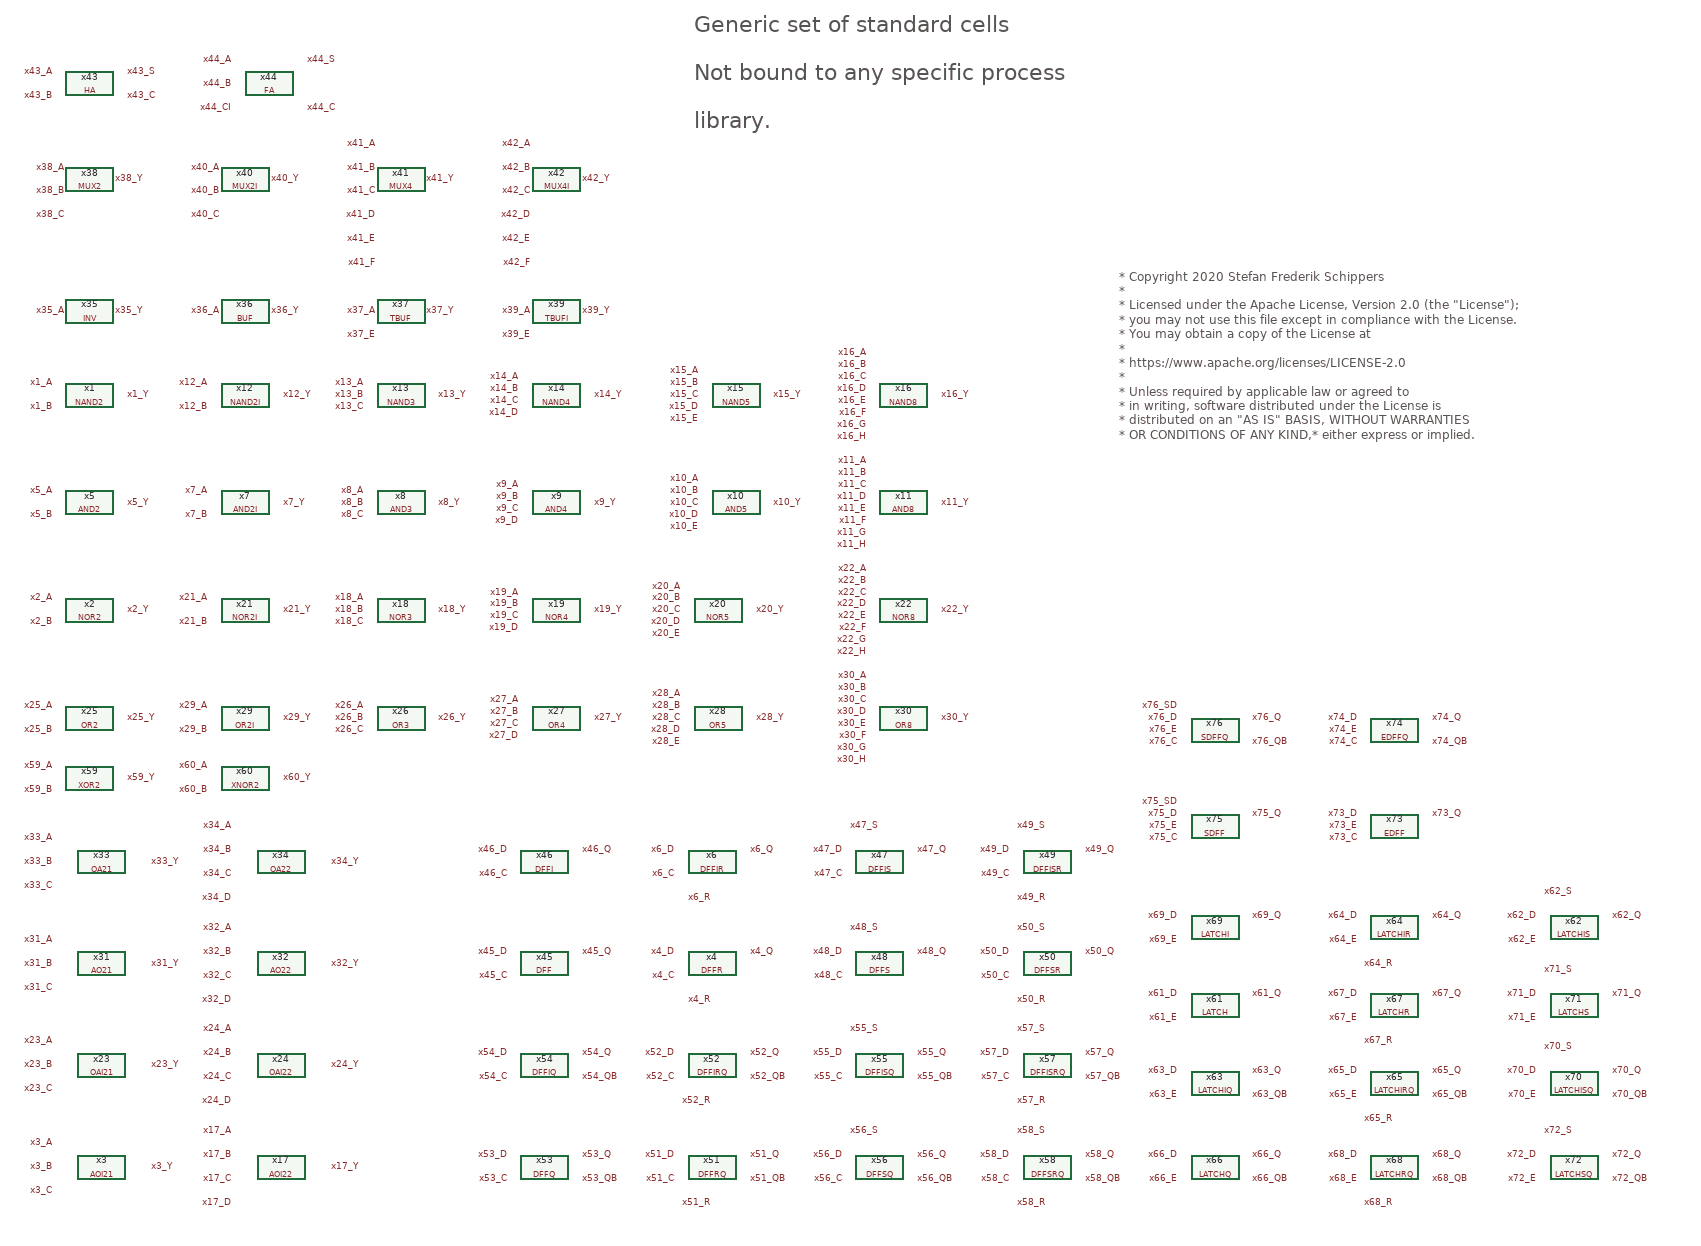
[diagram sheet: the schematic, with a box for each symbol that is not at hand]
v {xschem version=2.9.8 file_version=1.2

* Copyright 2020 Stefan Frederik Schippers
* 
* Licensed under the Apache License, Version 2.0 (the "License");
* you may not use this file except in compliance with the License.
* You may obtain a copy of the License at
*
*     https://www.apache.org/licenses/LICENSE-2.0
*
* Unless required by applicable law or agreed to in writing, software
* distributed under the License is distributed on an "AS IS" BASIS,
* WITHOUT WARRANTIES OR CONDITIONS OF ANY KIND, either express or implied.
* See the License for the specific language governing permissions and
* limitations under the License.

}
G {}
K {}
V {}
S {}
E {}
T {* Copyright 2020 Stefan Frederik Schippers
* 
* Licensed under the Apache License, Version 2.0 (the "License");
* you may not use this file except in compliance with the License.
* You may obtain a copy of the License at
*
*     https://www.apache.org/licenses/LICENSE-2.0
*
* Unless required by applicable law or agreed to
* in writing, software distributed under the License is
* distributed on an "AS IS" BASIS, WITHOUT WARRANTIES
* OR CONDITIONS OF ANY KIND,* either express or implied.
* See the License for the specific language governing
* permissions and limitations under the License.
} 1860 -1680 0 0 0.6 0.6 {}
T {Generic set of standard cells
Not bound to any specific process
library.} 1150 -2100 0 0 2 2 {layer=8}
C {stdcells/NAND2.sym} 140 -1470 0 0 {name=x1 VCCPIN=VCC VSSPIN=VSS VCCBPIN=VCC VSSBPIN=VSS}
C {stdcells/NOR2.sym} 140 -1110 0 0 {name=x2 VCCPIN=VCC VSSPIN=VSS VCCBPIN=VCC VSSBPIN=VSS}
C {stdcells/AOI21.sym} 160 -180 0 0 {name=x3 VCCPIN=VCC VSSPIN=VSS VCCBPIN=VCC VSSBPIN=VSS}
C {stdcells/DFFR.sym} 1180 -520 0 0 {name=x4 VCCPIN=VCC VSSPIN=VSS VCCBPIN=VCC VSSBPIN=VSS}
C {stdcells/AND2.sym} 140 -1290 0 0 {name=x5 VCCPIN=VCC VSSPIN=VSS VCCBPIN=VCC VSSBPIN=VSS}
C {stdcells/DFFIR.sym} 1180 -690 0 0 {name=x6 VCCPIN=VCC VSSPIN=VSS VCCBPIN=VCC VSSBPIN=VSS}
C {stdcells/AND2I.sym} 400 -1290 0 0 {name=x7 VCCPIN=VCC VSSPIN=VSS VCCBPIN=VCC VSSBPIN=VSS}
C {stdcells/AND3.sym} 660 -1290 0 0 {name=x8 VCCPIN=VCC VSSPIN=VSS VCCBPIN=VCC VSSBPIN=VSS}
C {stdcells/AND4.sym} 920 -1290 0 0 {name=x9 VCCPIN=VCC VSSPIN=VSS VCCBPIN=VCC VSSBPIN=VSS}
C {stdcells/AND5.sym} 1220 -1290 0 0 {name=x10 VCCPIN=VCC VSSPIN=VSS VCCBPIN=VCC VSSBPIN=VSS}
C {stdcells/AND8.sym} 1500 -1290 0 0 {name=x11 VCCPIN=VCC VSSPIN=VSS VCCBPIN=VCC VSSBPIN=VSS}
C {stdcells/NAND2I.sym} 400 -1470 0 0 {name=x12 VCCPIN=VCC VSSPIN=VSS VCCBPIN=VCC VSSBPIN=VSS}
C {stdcells/NAND3.sym} 660 -1470 0 0 {name=x13 VCCPIN=VCC VSSPIN=VSS VCCBPIN=VCC VSSBPIN=VSS}
C {stdcells/NAND4.sym} 920 -1470 0 0 {name=x14 VCCPIN=VCC VSSPIN=VSS VCCBPIN=VCC VSSBPIN=VSS}
C {stdcells/NAND5.sym} 1220 -1470 0 0 {name=x15 VCCPIN=VCC VSSPIN=VSS VCCBPIN=VCC VSSBPIN=VSS}
C {stdcells/NAND8.sym} 1500 -1470 0 0 {name=x16 VCCPIN=VCC VSSPIN=VSS VCCBPIN=VCC VSSBPIN=VSS}
C {stdcells/AOI22.sym} 460 -180 0 0 {name=x17 VCCPIN=VCC VSSPIN=VSS VCCBPIN=VCC VSSBPIN=VSS}
C {stdcells/NOR3.sym} 660 -1110 0 0 {name=x18 VCCPIN=VCC VSSPIN=VSS VCCBPIN=VCC VSSBPIN=VSS}
C {stdcells/NOR4.sym} 920 -1110 0 0 {name=x19 VCCPIN=VCC VSSPIN=VSS VCCBPIN=VCC VSSBPIN=VSS}
C {stdcells/NOR5.sym} 1190 -1110 0 0 {name=x20 VCCPIN=VCC VSSPIN=VSS VCCBPIN=VCC VSSBPIN=VSS}
C {stdcells/NOR2I.sym} 400 -1110 0 0 {name=x21 VCCPIN=VCC VSSPIN=VSS VCCBPIN=VCC VSSBPIN=VSS}
C {stdcells/NOR8.sym} 1500 -1110 0 0 {name=x22 VCCPIN=VCC VSSPIN=VSS VCCBPIN=VCC VSSBPIN=VSS}
C {stdcells/OAI21.sym} 160 -350 0 0 {name=x23 VCCPIN=VCC VSSPIN=VSS VCCBPIN=VCC VSSBPIN=VSS}
C {stdcells/OAI22.sym} 460 -350 0 0 {name=x24 VCCPIN=VCC VSSPIN=VSS VCCBPIN=VCC VSSBPIN=VSS}
C {stdcells/OR2.sym} 140 -930 0 0 {name=x25 VCCPIN=VCC VSSPIN=VSS VCCBPIN=VCC VSSBPIN=VSS}
C {stdcells/OR3.sym} 660 -930 0 0 {name=x26 VCCPIN=VCC VSSPIN=VSS VCCBPIN=VCC VSSBPIN=VSS}
C {stdcells/OR4.sym} 920 -930 0 0 {name=x27 VCCPIN=VCC VSSPIN=VSS VCCBPIN=VCC VSSBPIN=VSS}
C {stdcells/OR5.sym} 1190 -930 0 0 {name=x28 VCCPIN=VCC VSSPIN=VSS VCCBPIN=VCC VSSBPIN=VSS}
C {stdcells/OR2I.sym} 400 -930 0 0 {name=x29 VCCPIN=VCC VSSPIN=VSS VCCBPIN=VCC VSSBPIN=VSS}
C {stdcells/OR8.sym} 1500 -930 0 0 {name=x30 VCCPIN=VCC VSSPIN=VSS VCCBPIN=VCC VSSBPIN=VSS}
C {stdcells/AO21.sym} 160 -520 0 0 {name=x31 VCCPIN=VCC VSSPIN=VSS VCCBPIN=VCC VSSBPIN=VSS}
C {stdcells/AO22.sym} 460 -520 0 0 {name=x32 VCCPIN=VCC VSSPIN=VSS VCCBPIN=VCC VSSBPIN=VSS}
C {stdcells/OA21.sym} 160 -690 0 0 {name=x33 VCCPIN=VCC VSSPIN=VSS VCCBPIN=VCC VSSBPIN=VSS}
C {stdcells/OA22.sym} 460 -690 0 0 {name=x34 VCCPIN=VCC VSSPIN=VSS VCCBPIN=VCC VSSBPIN=VSS}
C {stdcells/INV.sym} 140 -1610 0 0 {name=x35 VCCPIN=VCC VSSPIN=VSS VCCBPIN=VCC VSSBPIN=VSS}
C {stdcells/BUF.sym} 400 -1610 0 0 {name=x36 VCCPIN=VCC VSSPIN=VSS VCCBPIN=VCC VSSBPIN=VSS}
C {stdcells/TBUF.sym} 660 -1610 0 0 {name=x37 VCCPIN=VCC VSSPIN=VSS VCCBPIN=VCC VSSBPIN=VSS}
C {stdcells/TBUFI.sym} 920 -1610 0 0 {name=x39 VCCPIN=VCC VSSPIN=VSS VCCBPIN=VCC VSSBPIN=VSS}
C {stdcells/MUX2.sym} 140 -1830 0 0 {name=x38 VCCPIN=VCC VSSPIN=VSS VCCBPIN=VCC VSSBPIN=VSS}
C {stdcells/MUX2I.sym} 400 -1830 0 0 {name=x40 VCCPIN=VCC VSSPIN=VSS VCCBPIN=VCC VSSBPIN=VSS}
C {stdcells/MUX4.sym} 660 -1830 0 0 {name=x41 VCCPIN=VCC VSSPIN=VSS VCCBPIN=VCC VSSBPIN=VSS}
C {stdcells/MUX4I.sym} 920 -1830 0 0 {name=x42 VCCPIN=VCC VSSPIN=VSS VCCBPIN=VCC VSSBPIN=VSS}
C {stdcells/HA.sym} 140 -1990 0 0 {name=x43 VCCPIN=VCC VSSPIN=VSS VCCBPIN=VCC VSSBPIN=VSS}
C {stdcells/FA.sym} 440 -1990 0 0 {name=x44 VCCPIN=VCC VSSPIN=VSS VCCBPIN=VCC VSSBPIN=VSS}
C {stdcells/DFF.sym} 900 -520 0 0 {name=x45 VCCPIN=VCC VSSPIN=VSS VCCBPIN=VCC VSSBPIN=VSS}
C {stdcells/DFFI.sym} 900 -690 0 0 {name=x46 VCCPIN=VCC VSSPIN=VSS VCCBPIN=VCC VSSBPIN=VSS}
C {stdcells/DFFIS.sym} 1460 -690 0 0 {name=x47 VCCPIN=VCC VSSPIN=VSS VCCBPIN=VCC VSSBPIN=VSS}
C {stdcells/DFFS.sym} 1460 -520 0 0 {name=x48 VCCPIN=VCC VSSPIN=VSS VCCBPIN=VCC VSSBPIN=VSS}
C {stdcells/DFFISR.sym} 1740 -690 0 0 {name=x49 VCCPIN=VCC VSSPIN=VSS VCCBPIN=VCC VSSBPIN=VSS}
C {stdcells/DFFSR.sym} 1740 -520 0 0 {name=x50 VCCPIN=VCC VSSPIN=VSS VCCBPIN=VCC VSSBPIN=VSS}
C {stdcells/DFFRQ.sym} 1180 -180 0 0 {name=x51 VCCPIN=VCC VSSPIN=VSS VCCBPIN=VCC VSSBPIN=VSS}
C {stdcells/DFFIRQ.sym} 1180 -350 0 0 {name=x52 VCCPIN=VCC VSSPIN=VSS VCCBPIN=VCC VSSBPIN=VSS}
C {stdcells/DFFQ.sym} 900 -180 0 0 {name=x53 VCCPIN=VCC VSSPIN=VSS VCCBPIN=VCC VSSBPIN=VSS}
C {stdcells/DFFIQ.sym} 900 -350 0 0 {name=x54 VCCPIN=VCC VSSPIN=VSS VCCBPIN=VCC VSSBPIN=VSS}
C {stdcells/DFFISQ.sym} 1460 -350 0 0 {name=x55 VCCPIN=VCC VSSPIN=VSS VCCBPIN=VCC VSSBPIN=VSS}
C {stdcells/DFFSQ.sym} 1460 -180 0 0 {name=x56 VCCPIN=VCC VSSPIN=VSS VCCBPIN=VCC VSSBPIN=VSS}
C {stdcells/DFFISRQ.sym} 1740 -350 0 0 {name=x57 VCCPIN=VCC VSSPIN=VSS VCCBPIN=VCC VSSBPIN=VSS}
C {stdcells/DFFSRQ.sym} 1740 -180 0 0 {name=x58 VCCPIN=VCC VSSPIN=VSS VCCBPIN=VCC VSSBPIN=VSS}
C {stdcells/XOR2.sym} 140 -830 0 0 {name=x59 VCCPIN=VCC VSSPIN=VSS VCCBPIN=VCC VSSBPIN=VSS}
C {stdcells/XNOR2.sym} 400 -830 0 0 {name=x60 VCCPIN=VCC VSSPIN=VSS VCCBPIN=VCC VSSBPIN=VSS}
C {stdcells/LATCH.sym} 2020 -450 0 0 {name=x61 VCCPIN=VCC VSSPIN=VSS VCCBPIN=VCC VSSBPIN=VSS}
C {stdcells/LATCHIQ.sym} 2020 -320 0 0 {name=x63 VCCPIN=VCC VSSPIN=VSS VCCBPIN=VCC VSSBPIN=VSS}
C {stdcells/LATCHIR.sym} 2320 -580 0 0 {name=x64 VCCPIN=VCC VSSPIN=VSS VCCBPIN=VCC VSSBPIN=VSS}
C {stdcells/LATCHIRQ.sym} 2320 -320 0 0 {name=x65 VCCPIN=VCC VSSPIN=VSS VCCBPIN=VCC VSSBPIN=VSS}
C {stdcells/LATCHQ.sym} 2020 -180 0 0 {name=x66 VCCPIN=VCC VSSPIN=VSS VCCBPIN=VCC VSSBPIN=VSS}
C {stdcells/LATCHR.sym} 2320 -450 0 0 {name=x67 VCCPIN=VCC VSSPIN=VSS VCCBPIN=VCC VSSBPIN=VSS}
C {stdcells/LATCHRQ.sym} 2320 -180 0 0 {name=x68 VCCPIN=VCC VSSPIN=VSS VCCBPIN=VCC VSSBPIN=VSS}
C {stdcells/LATCHI.sym} 2020 -580 0 0 {name=x69 VCCPIN=VCC VSSPIN=VSS VCCBPIN=VCC VSSBPIN=VSS}
C {stdcells/LATCHIS.sym} 2620 -580 0 0 {name=x62 VCCPIN=VCC VSSPIN=VSS VCCBPIN=VCC VSSBPIN=VSS}
C {stdcells/LATCHISQ.sym} 2620 -320 0 0 {name=x70 VCCPIN=VCC VSSPIN=VSS VCCBPIN=VCC VSSBPIN=VSS}
C {stdcells/LATCHS.sym} 2620 -450 0 0 {name=x71 VCCPIN=VCC VSSPIN=VSS VCCBPIN=VCC VSSBPIN=VSS}
C {stdcells/LATCHSQ.sym} 2620 -180 0 0 {name=x72 VCCPIN=VCC VSSPIN=VSS VCCBPIN=VCC VSSBPIN=VSS}
C {stdcells/EDFF.sym} 2320 -750 0 0 {name=x73 VCCPIN=VCC VSSPIN=VSS VCCBPIN=VCC VSSBPIN=VSS}
C {stdcells/EDFFQ.sym} 2320 -910 0 0 {name=x74 VCCPIN=VCC VSSPIN=VSS VCCBPIN=VCC VSSBPIN=VSS}
C {stdcells/SDFF.sym} 2020 -750 0 0 {name=x75 VCCPIN=VCC VSSPIN=VSS VCCBPIN=VCC VSSBPIN=VSS}
C {stdcells/SDFFQ.sym} 2020 -910 0 0 {name=x76 VCCPIN=VCC VSSPIN=VSS VCCBPIN=VCC VSSBPIN=VSS}
C {devices/title.sym} 160 -30 0 0 {name=l1 author="Stefan Schippers"}
C {devices/lab_pin.sym} 200 -1470 0 1 {name=p1 lab=x1_Y}
C {devices/lab_pin.sym} 80 -1490 0 0 {name=p2 lab=x1_A}
C {devices/lab_pin.sym} 80 -1450 0 0 {name=p3 lab=x1_B}
C {devices/lab_pin.sym} 200 -1110 0 1 {name=p4 lab=x2_Y}
C {devices/lab_pin.sym} 80 -1130 0 0 {name=p5 lab=x2_A}
C {devices/lab_pin.sym} 80 -1090 0 0 {name=p6 lab=x2_B}
C {devices/lab_pin.sym} 240 -180 0 1 {name=p7 lab=x3_Y}
C {devices/lab_pin.sym} 80 -220 0 0 {name=p8 lab=x3_A}
C {devices/lab_pin.sym} 80 -180 0 0 {name=p9 lab=x3_B}
C {devices/lab_pin.sym} 80 -140 0 0 {name=p10 lab=x3_C}
C {devices/lab_pin.sym} 1240 -540 0 1 {name=p11 lab=x4_Q}
C {devices/lab_pin.sym} 1120 -540 0 0 {name=p12 lab=x4_D}
C {devices/lab_pin.sym} 1120 -500 0 0 {name=p13 lab=x4_C}
C {devices/lab_pin.sym} 1180 -460 0 0 {name=p14 lab=x4_R}
C {devices/lab_pin.sym} 200 -1290 0 1 {name=p15 lab=x5_Y}
C {devices/lab_pin.sym} 80 -1310 0 0 {name=p16 lab=x5_A}
C {devices/lab_pin.sym} 80 -1270 0 0 {name=p17 lab=x5_B}
C {devices/lab_pin.sym} 1240 -710 0 1 {name=p18 lab=x6_Q}
C {devices/lab_pin.sym} 1120 -710 0 0 {name=p19 lab=x6_D}
C {devices/lab_pin.sym} 1120 -670 0 0 {name=p20 lab=x6_C}
C {devices/lab_pin.sym} 1180 -630 0 0 {name=p21 lab=x6_R}
C {devices/lab_pin.sym} 460 -1290 0 1 {name=p22 lab=x7_Y}
C {devices/lab_pin.sym} 340 -1310 0 0 {name=p23 lab=x7_A}
C {devices/lab_pin.sym} 340 -1270 0 0 {name=p24 lab=x7_B}
C {devices/lab_pin.sym} 720 -1290 0 1 {name=p25 lab=x8_Y}
C {devices/lab_pin.sym} 600 -1310 0 0 {name=p26 lab=x8_A}
C {devices/lab_pin.sym} 600 -1290 0 0 {name=p27 lab=x8_B}
C {devices/lab_pin.sym} 600 -1270 0 0 {name=p28 lab=x8_C}
C {devices/lab_pin.sym} 980 -1290 0 1 {name=p29 lab=x9_Y}
C {devices/lab_pin.sym} 860 -1320 0 0 {name=p30 lab=x9_A}
C {devices/lab_pin.sym} 860 -1300 0 0 {name=p31 lab=x9_B}
C {devices/lab_pin.sym} 860 -1280 0 0 {name=p32 lab=x9_C}
C {devices/lab_pin.sym} 860 -1260 0 0 {name=p33 lab=x9_D}
C {devices/lab_pin.sym} 1280 -1290 0 1 {name=p34 lab=x10_Y}
C {devices/lab_pin.sym} 1160 -1330 0 0 {name=p35 lab=x10_A}
C {devices/lab_pin.sym} 1160 -1310 0 0 {name=p36 lab=x10_B}
C {devices/lab_pin.sym} 1160 -1290 0 0 {name=p37 lab=x10_C}
C {devices/lab_pin.sym} 1160 -1270 0 0 {name=p38 lab=x10_D}
C {devices/lab_pin.sym} 1160 -1250 0 0 {name=p39 lab=x10_E}
C {devices/lab_pin.sym} 1560 -1290 0 1 {name=p40 lab=x11_Y}
C {devices/lab_pin.sym} 1440 -1360 0 0 {name=p41 lab=x11_A}
C {devices/lab_pin.sym} 1440 -1340 0 0 {name=p42 lab=x11_B}
C {devices/lab_pin.sym} 1440 -1320 0 0 {name=p43 lab=x11_C}
C {devices/lab_pin.sym} 1440 -1300 0 0 {name=p44 lab=x11_D}
C {devices/lab_pin.sym} 1440 -1280 0 0 {name=p45 lab=x11_E}
C {devices/lab_pin.sym} 1440 -1260 0 0 {name=p46 lab=x11_F}
C {devices/lab_pin.sym} 1440 -1240 0 0 {name=p47 lab=x11_G}
C {devices/lab_pin.sym} 1440 -1220 0 0 {name=p48 lab=x11_H}
C {devices/lab_pin.sym} 460 -1470 0 1 {name=p49 lab=x12_Y}
C {devices/lab_pin.sym} 340 -1490 0 0 {name=p50 lab=x12_A}
C {devices/lab_pin.sym} 340 -1450 0 0 {name=p51 lab=x12_B}
C {devices/lab_pin.sym} 720 -1470 0 1 {name=p52 lab=x13_Y}
C {devices/lab_pin.sym} 600 -1490 0 0 {name=p53 lab=x13_A}
C {devices/lab_pin.sym} 600 -1470 0 0 {name=p54 lab=x13_B}
C {devices/lab_pin.sym} 600 -1450 0 0 {name=p55 lab=x13_C}
C {devices/lab_pin.sym} 980 -1470 0 1 {name=p56 lab=x14_Y}
C {devices/lab_pin.sym} 860 -1500 0 0 {name=p57 lab=x14_A}
C {devices/lab_pin.sym} 860 -1480 0 0 {name=p58 lab=x14_B}
C {devices/lab_pin.sym} 860 -1460 0 0 {name=p59 lab=x14_C}
C {devices/lab_pin.sym} 860 -1440 0 0 {name=p60 lab=x14_D}
C {devices/lab_pin.sym} 1280 -1470 0 1 {name=p61 lab=x15_Y}
C {devices/lab_pin.sym} 1160 -1510 0 0 {name=p62 lab=x15_A}
C {devices/lab_pin.sym} 1160 -1490 0 0 {name=p63 lab=x15_B}
C {devices/lab_pin.sym} 1160 -1470 0 0 {name=p64 lab=x15_C}
C {devices/lab_pin.sym} 1160 -1450 0 0 {name=p65 lab=x15_D}
C {devices/lab_pin.sym} 1160 -1430 0 0 {name=p66 lab=x15_E}
C {devices/lab_pin.sym} 1560 -1470 0 1 {name=p67 lab=x16_Y}
C {devices/lab_pin.sym} 1440 -1540 0 0 {name=p68 lab=x16_A}
C {devices/lab_pin.sym} 1440 -1520 0 0 {name=p69 lab=x16_B}
C {devices/lab_pin.sym} 1440 -1500 0 0 {name=p70 lab=x16_C}
C {devices/lab_pin.sym} 1440 -1480 0 0 {name=p71 lab=x16_D}
C {devices/lab_pin.sym} 1440 -1460 0 0 {name=p72 lab=x16_E}
C {devices/lab_pin.sym} 1440 -1440 0 0 {name=p73 lab=x16_F}
C {devices/lab_pin.sym} 1440 -1420 0 0 {name=p74 lab=x16_G}
C {devices/lab_pin.sym} 1440 -1400 0 0 {name=p75 lab=x16_H}
C {devices/lab_pin.sym} 540 -180 0 1 {name=p76 lab=x17_Y}
C {devices/lab_pin.sym} 380 -240 0 0 {name=p77 lab=x17_A}
C {devices/lab_pin.sym} 380 -200 0 0 {name=p78 lab=x17_B}
C {devices/lab_pin.sym} 380 -160 0 0 {name=p79 lab=x17_C}
C {devices/lab_pin.sym} 380 -120 0 0 {name=p80 lab=x17_D}
C {devices/lab_pin.sym} 720 -1110 0 1 {name=p81 lab=x18_Y}
C {devices/lab_pin.sym} 600 -1130 0 0 {name=p82 lab=x18_A}
C {devices/lab_pin.sym} 600 -1110 0 0 {name=p83 lab=x18_B}
C {devices/lab_pin.sym} 600 -1090 0 0 {name=p84 lab=x18_C}
C {devices/lab_pin.sym} 980 -1110 0 1 {name=p85 lab=x19_Y}
C {devices/lab_pin.sym} 860 -1140 0 0 {name=p86 lab=x19_A}
C {devices/lab_pin.sym} 860 -1120 0 0 {name=p87 lab=x19_B}
C {devices/lab_pin.sym} 860 -1100 0 0 {name=p88 lab=x19_C}
C {devices/lab_pin.sym} 860 -1080 0 0 {name=p89 lab=x19_D}
C {devices/lab_pin.sym} 1250 -1110 0 1 {name=p90 lab=x20_Y}
C {devices/lab_pin.sym} 1130 -1150 0 0 {name=p91 lab=x20_A}
C {devices/lab_pin.sym} 1130 -1130 0 0 {name=p92 lab=x20_B}
C {devices/lab_pin.sym} 1130 -1110 0 0 {name=p93 lab=x20_C}
C {devices/lab_pin.sym} 1130 -1090 0 0 {name=p94 lab=x20_D}
C {devices/lab_pin.sym} 1130 -1070 0 0 {name=p95 lab=x20_E}
C {devices/lab_pin.sym} 460 -1110 0 1 {name=p96 lab=x21_Y}
C {devices/lab_pin.sym} 340 -1130 0 0 {name=p97 lab=x21_A}
C {devices/lab_pin.sym} 340 -1090 0 0 {name=p98 lab=x21_B}
C {devices/lab_pin.sym} 1560 -1110 0 1 {name=p99 lab=x22_Y}
C {devices/lab_pin.sym} 1440 -1180 0 0 {name=p100 lab=x22_A}
C {devices/lab_pin.sym} 1440 -1160 0 0 {name=p101 lab=x22_B}
C {devices/lab_pin.sym} 1440 -1140 0 0 {name=p102 lab=x22_C}
C {devices/lab_pin.sym} 1440 -1120 0 0 {name=p103 lab=x22_D}
C {devices/lab_pin.sym} 1440 -1100 0 0 {name=p104 lab=x22_E}
C {devices/lab_pin.sym} 1440 -1080 0 0 {name=p105 lab=x22_F}
C {devices/lab_pin.sym} 1440 -1060 0 0 {name=p106 lab=x22_G}
C {devices/lab_pin.sym} 1440 -1040 0 0 {name=p107 lab=x22_H}
C {devices/lab_pin.sym} 240 -350 0 1 {name=p108 lab=x23_Y}
C {devices/lab_pin.sym} 80 -390 0 0 {name=p109 lab=x23_A}
C {devices/lab_pin.sym} 80 -350 0 0 {name=p110 lab=x23_B}
C {devices/lab_pin.sym} 80 -310 0 0 {name=p111 lab=x23_C}
C {devices/lab_pin.sym} 540 -350 0 1 {name=p112 lab=x24_Y}
C {devices/lab_pin.sym} 380 -410 0 0 {name=p113 lab=x24_A}
C {devices/lab_pin.sym} 380 -370 0 0 {name=p114 lab=x24_B}
C {devices/lab_pin.sym} 380 -330 0 0 {name=p115 lab=x24_C}
C {devices/lab_pin.sym} 380 -290 0 0 {name=p116 lab=x24_D}
C {devices/lab_pin.sym} 200 -930 0 1 {name=p117 lab=x25_Y}
C {devices/lab_pin.sym} 80 -950 0 0 {name=p118 lab=x25_A}
C {devices/lab_pin.sym} 80 -910 0 0 {name=p119 lab=x25_B}
C {devices/lab_pin.sym} 720 -930 0 1 {name=p120 lab=x26_Y}
C {devices/lab_pin.sym} 600 -950 0 0 {name=p121 lab=x26_A}
C {devices/lab_pin.sym} 600 -930 0 0 {name=p122 lab=x26_B}
C {devices/lab_pin.sym} 600 -910 0 0 {name=p123 lab=x26_C}
C {devices/lab_pin.sym} 980 -930 0 1 {name=p124 lab=x27_Y}
C {devices/lab_pin.sym} 860 -960 0 0 {name=p125 lab=x27_A}
C {devices/lab_pin.sym} 860 -940 0 0 {name=p126 lab=x27_B}
C {devices/lab_pin.sym} 860 -920 0 0 {name=p127 lab=x27_C}
C {devices/lab_pin.sym} 860 -900 0 0 {name=p128 lab=x27_D}
C {devices/lab_pin.sym} 1250 -930 0 1 {name=p129 lab=x28_Y}
C {devices/lab_pin.sym} 1130 -970 0 0 {name=p130 lab=x28_A}
C {devices/lab_pin.sym} 1130 -950 0 0 {name=p131 lab=x28_B}
C {devices/lab_pin.sym} 1130 -930 0 0 {name=p132 lab=x28_C}
C {devices/lab_pin.sym} 1130 -910 0 0 {name=p133 lab=x28_D}
C {devices/lab_pin.sym} 1130 -890 0 0 {name=p134 lab=x28_E}
C {devices/lab_pin.sym} 460 -930 0 1 {name=p135 lab=x29_Y}
C {devices/lab_pin.sym} 340 -950 0 0 {name=p136 lab=x29_A}
C {devices/lab_pin.sym} 340 -910 0 0 {name=p137 lab=x29_B}
C {devices/lab_pin.sym} 1560 -930 0 1 {name=p138 lab=x30_Y}
C {devices/lab_pin.sym} 1440 -1000 0 0 {name=p139 lab=x30_A}
C {devices/lab_pin.sym} 1440 -980 0 0 {name=p140 lab=x30_B}
C {devices/lab_pin.sym} 1440 -960 0 0 {name=p141 lab=x30_C}
C {devices/lab_pin.sym} 1440 -940 0 0 {name=p142 lab=x30_D}
C {devices/lab_pin.sym} 1440 -920 0 0 {name=p143 lab=x30_E}
C {devices/lab_pin.sym} 1440 -900 0 0 {name=p144 lab=x30_F}
C {devices/lab_pin.sym} 1440 -880 0 0 {name=p145 lab=x30_G}
C {devices/lab_pin.sym} 1440 -860 0 0 {name=p146 lab=x30_H}
C {devices/lab_pin.sym} 240 -520 0 1 {name=p147 lab=x31_Y}
C {devices/lab_pin.sym} 80 -560 0 0 {name=p148 lab=x31_A}
C {devices/lab_pin.sym} 80 -520 0 0 {name=p149 lab=x31_B}
C {devices/lab_pin.sym} 80 -480 0 0 {name=p150 lab=x31_C}
C {devices/lab_pin.sym} 540 -520 0 1 {name=p151 lab=x32_Y}
C {devices/lab_pin.sym} 380 -580 0 0 {name=p152 lab=x32_A}
C {devices/lab_pin.sym} 380 -540 0 0 {name=p153 lab=x32_B}
C {devices/lab_pin.sym} 380 -500 0 0 {name=p154 lab=x32_C}
C {devices/lab_pin.sym} 380 -460 0 0 {name=p155 lab=x32_D}
C {devices/lab_pin.sym} 240 -690 0 1 {name=p156 lab=x33_Y}
C {devices/lab_pin.sym} 80 -730 0 0 {name=p157 lab=x33_A}
C {devices/lab_pin.sym} 80 -690 0 0 {name=p158 lab=x33_B}
C {devices/lab_pin.sym} 80 -650 0 0 {name=p159 lab=x33_C}
C {devices/lab_pin.sym} 540 -690 0 1 {name=p160 lab=x34_Y}
C {devices/lab_pin.sym} 380 -750 0 0 {name=p161 lab=x34_A}
C {devices/lab_pin.sym} 380 -710 0 0 {name=p162 lab=x34_B}
C {devices/lab_pin.sym} 380 -670 0 0 {name=p163 lab=x34_C}
C {devices/lab_pin.sym} 380 -630 0 0 {name=p164 lab=x34_D}
C {devices/lab_pin.sym} 180 -1610 0 1 {name=p165 lab=x35_Y}
C {devices/lab_pin.sym} 100 -1610 0 0 {name=p166 lab=x35_A}
C {devices/lab_pin.sym} 440 -1610 0 1 {name=p167 lab=x36_Y}
C {devices/lab_pin.sym} 360 -1610 0 0 {name=p168 lab=x36_A}
C {devices/lab_pin.sym} 700 -1610 0 1 {name=p169 lab=x37_Y}
C {devices/lab_pin.sym} 620 -1610 0 0 {name=p170 lab=x37_A}
C {devices/lab_pin.sym} 620 -1570 0 0 {name=p171 lab=x37_E}
C {devices/lab_pin.sym} 960 -1610 0 1 {name=p172 lab=x39_Y}
C {devices/lab_pin.sym} 880 -1610 0 0 {name=p173 lab=x39_A}
C {devices/lab_pin.sym} 880 -1570 0 0 {name=p174 lab=x39_E}
C {devices/lab_pin.sym} 180 -1830 0 1 {name=p175 lab=x38_Y}
C {devices/lab_pin.sym} 100 -1850 0 0 {name=p176 lab=x38_A}
C {devices/lab_pin.sym} 100 -1810 0 0 {name=p177 lab=x38_B}
C {devices/lab_pin.sym} 100 -1770 0 0 {name=p178 lab=x38_C}
C {devices/lab_pin.sym} 440 -1830 0 1 {name=p179 lab=x40_Y}
C {devices/lab_pin.sym} 360 -1850 0 0 {name=p180 lab=x40_A}
C {devices/lab_pin.sym} 360 -1810 0 0 {name=p181 lab=x40_B}
C {devices/lab_pin.sym} 360 -1770 0 0 {name=p182 lab=x40_C}
C {devices/lab_pin.sym} 700 -1830 0 1 {name=p183 lab=x41_Y}
C {devices/lab_pin.sym} 620 -1890 0 0 {name=p184 lab=x41_A}
C {devices/lab_pin.sym} 620 -1850 0 0 {name=p185 lab=x41_B}
C {devices/lab_pin.sym} 620 -1810 0 0 {name=p186 lab=x41_C}
C {devices/lab_pin.sym} 620 -1770 0 0 {name=p187 lab=x41_D}
C {devices/lab_pin.sym} 620 -1730 0 0 {name=p188 lab=x41_E}
C {devices/lab_pin.sym} 620 -1690 0 0 {name=p189 lab=x41_F}
C {devices/lab_pin.sym} 960 -1830 0 1 {name=p190 lab=x42_Y}
C {devices/lab_pin.sym} 880 -1890 0 0 {name=p191 lab=x42_A}
C {devices/lab_pin.sym} 880 -1850 0 0 {name=p192 lab=x42_B}
C {devices/lab_pin.sym} 880 -1810 0 0 {name=p193 lab=x42_C}
C {devices/lab_pin.sym} 880 -1770 0 0 {name=p194 lab=x42_D}
C {devices/lab_pin.sym} 880 -1730 0 0 {name=p195 lab=x42_E}
C {devices/lab_pin.sym} 880 -1690 0 0 {name=p196 lab=x42_F}
C {devices/lab_pin.sym} 200 -2010 0 1 {name=p197 lab=x43_S}
C {devices/lab_pin.sym} 200 -1970 0 1 {name=p198 lab=x43_C}
C {devices/lab_pin.sym} 80 -2010 0 0 {name=p199 lab=x43_A}
C {devices/lab_pin.sym} 80 -1970 0 0 {name=p200 lab=x43_B}
C {devices/lab_pin.sym} 500 -2030 0 1 {name=p201 lab=x44_S}
C {devices/lab_pin.sym} 500 -1950 0 1 {name=p202 lab=x44_C}
C {devices/lab_pin.sym} 380 -2030 0 0 {name=p203 lab=x44_A}
C {devices/lab_pin.sym} 380 -1990 0 0 {name=p204 lab=x44_B}
C {devices/lab_pin.sym} 380 -1950 0 0 {name=p205 lab=x44_CI}
C {devices/lab_pin.sym} 960 -540 0 1 {name=p206 lab=x45_Q}
C {devices/lab_pin.sym} 840 -540 0 0 {name=p207 lab=x45_D}
C {devices/lab_pin.sym} 840 -500 0 0 {name=p208 lab=x45_C}
C {devices/lab_pin.sym} 960 -710 0 1 {name=p209 lab=x46_Q}
C {devices/lab_pin.sym} 840 -710 0 0 {name=p210 lab=x46_D}
C {devices/lab_pin.sym} 840 -670 0 0 {name=p211 lab=x46_C}
C {devices/lab_pin.sym} 1520 -710 0 1 {name=p212 lab=x47_Q}
C {devices/lab_pin.sym} 1400 -710 0 0 {name=p213 lab=x47_D}
C {devices/lab_pin.sym} 1400 -670 0 0 {name=p214 lab=x47_C}
C {devices/lab_pin.sym} 1460 -750 0 0 {name=p215 lab=x47_S}
C {devices/lab_pin.sym} 1520 -540 0 1 {name=p216 lab=x48_Q}
C {devices/lab_pin.sym} 1400 -540 0 0 {name=p217 lab=x48_D}
C {devices/lab_pin.sym} 1400 -500 0 0 {name=p218 lab=x48_C}
C {devices/lab_pin.sym} 1460 -580 0 0 {name=p219 lab=x48_S}
C {devices/lab_pin.sym} 1800 -710 0 1 {name=p220 lab=x49_Q}
C {devices/lab_pin.sym} 1680 -710 0 0 {name=p221 lab=x49_D}
C {devices/lab_pin.sym} 1680 -670 0 0 {name=p222 lab=x49_C}
C {devices/lab_pin.sym} 1740 -750 0 0 {name=p223 lab=x49_S}
C {devices/lab_pin.sym} 1740 -630 0 0 {name=p224 lab=x49_R}
C {devices/lab_pin.sym} 1800 -540 0 1 {name=p225 lab=x50_Q}
C {devices/lab_pin.sym} 1680 -540 0 0 {name=p226 lab=x50_D}
C {devices/lab_pin.sym} 1680 -500 0 0 {name=p227 lab=x50_C}
C {devices/lab_pin.sym} 1740 -580 0 0 {name=p228 lab=x50_S}
C {devices/lab_pin.sym} 1740 -460 0 0 {name=p229 lab=x50_R}
C {devices/lab_pin.sym} 1240 -200 0 1 {name=p230 lab=x51_Q}
C {devices/lab_pin.sym} 1240 -160 0 1 {name=p231 lab=x51_QB}
C {devices/lab_pin.sym} 1120 -200 0 0 {name=p232 lab=x51_D}
C {devices/lab_pin.sym} 1120 -160 0 0 {name=p233 lab=x51_C}
C {devices/lab_pin.sym} 1180 -120 0 0 {name=p234 lab=x51_R}
C {devices/lab_pin.sym} 1240 -370 0 1 {name=p235 lab=x52_Q}
C {devices/lab_pin.sym} 1240 -330 0 1 {name=p236 lab=x52_QB}
C {devices/lab_pin.sym} 1120 -370 0 0 {name=p237 lab=x52_D}
C {devices/lab_pin.sym} 1120 -330 0 0 {name=p238 lab=x52_C}
C {devices/lab_pin.sym} 1180 -290 0 0 {name=p239 lab=x52_R}
C {devices/lab_pin.sym} 960 -200 0 1 {name=p240 lab=x53_Q}
C {devices/lab_pin.sym} 960 -160 0 1 {name=p241 lab=x53_QB}
C {devices/lab_pin.sym} 840 -200 0 0 {name=p242 lab=x53_D}
C {devices/lab_pin.sym} 840 -160 0 0 {name=p243 lab=x53_C}
C {devices/lab_pin.sym} 960 -370 0 1 {name=p244 lab=x54_Q}
C {devices/lab_pin.sym} 960 -330 0 1 {name=p245 lab=x54_QB}
C {devices/lab_pin.sym} 840 -370 0 0 {name=p246 lab=x54_D}
C {devices/lab_pin.sym} 840 -330 0 0 {name=p247 lab=x54_C}
C {devices/lab_pin.sym} 1520 -370 0 1 {name=p248 lab=x55_Q}
C {devices/lab_pin.sym} 1520 -330 0 1 {name=p249 lab=x55_QB}
C {devices/lab_pin.sym} 1400 -370 0 0 {name=p250 lab=x55_D}
C {devices/lab_pin.sym} 1400 -330 0 0 {name=p251 lab=x55_C}
C {devices/lab_pin.sym} 1460 -410 0 0 {name=p252 lab=x55_S}
C {devices/lab_pin.sym} 1520 -200 0 1 {name=p253 lab=x56_Q}
C {devices/lab_pin.sym} 1520 -160 0 1 {name=p254 lab=x56_QB}
C {devices/lab_pin.sym} 1400 -200 0 0 {name=p255 lab=x56_D}
C {devices/lab_pin.sym} 1400 -160 0 0 {name=p256 lab=x56_C}
C {devices/lab_pin.sym} 1460 -240 0 0 {name=p257 lab=x56_S}
C {devices/lab_pin.sym} 1800 -370 0 1 {name=p258 lab=x57_Q}
C {devices/lab_pin.sym} 1800 -330 0 1 {name=p259 lab=x57_QB}
C {devices/lab_pin.sym} 1680 -370 0 0 {name=p260 lab=x57_D}
C {devices/lab_pin.sym} 1680 -330 0 0 {name=p261 lab=x57_C}
C {devices/lab_pin.sym} 1740 -410 0 0 {name=p262 lab=x57_S}
C {devices/lab_pin.sym} 1740 -290 0 0 {name=p263 lab=x57_R}
C {devices/lab_pin.sym} 1800 -200 0 1 {name=p264 lab=x58_Q}
C {devices/lab_pin.sym} 1800 -160 0 1 {name=p265 lab=x58_QB}
C {devices/lab_pin.sym} 1680 -200 0 0 {name=p266 lab=x58_D}
C {devices/lab_pin.sym} 1680 -160 0 0 {name=p267 lab=x58_C}
C {devices/lab_pin.sym} 1740 -240 0 0 {name=p268 lab=x58_S}
C {devices/lab_pin.sym} 1740 -120 0 0 {name=p269 lab=x58_R}
C {devices/lab_pin.sym} 200 -830 0 1 {name=p270 lab=x59_Y}
C {devices/lab_pin.sym} 80 -850 0 0 {name=p271 lab=x59_A}
C {devices/lab_pin.sym} 80 -810 0 0 {name=p272 lab=x59_B}
C {devices/lab_pin.sym} 460 -830 0 1 {name=p273 lab=x60_Y}
C {devices/lab_pin.sym} 340 -850 0 0 {name=p274 lab=x60_A}
C {devices/lab_pin.sym} 340 -810 0 0 {name=p275 lab=x60_B}
C {devices/lab_pin.sym} 2080 -470 0 1 {name=p276 lab=x61_Q}
C {devices/lab_pin.sym} 1960 -470 0 0 {name=p277 lab=x61_D}
C {devices/lab_pin.sym} 1960 -430 0 0 {name=p278 lab=x61_E}
C {devices/lab_pin.sym} 2080 -340 0 1 {name=p279 lab=x63_Q}
C {devices/lab_pin.sym} 2080 -300 0 1 {name=p280 lab=x63_QB}
C {devices/lab_pin.sym} 1960 -340 0 0 {name=p281 lab=x63_D}
C {devices/lab_pin.sym} 1960 -300 0 0 {name=p282 lab=x63_E}
C {devices/lab_pin.sym} 2380 -600 0 1 {name=p283 lab=x64_Q}
C {devices/lab_pin.sym} 2260 -600 0 0 {name=p284 lab=x64_D}
C {devices/lab_pin.sym} 2260 -560 0 0 {name=p285 lab=x64_E}
C {devices/lab_pin.sym} 2320 -520 0 0 {name=p286 lab=x64_R}
C {devices/lab_pin.sym} 2380 -340 0 1 {name=p287 lab=x65_Q}
C {devices/lab_pin.sym} 2380 -300 0 1 {name=p288 lab=x65_QB}
C {devices/lab_pin.sym} 2260 -340 0 0 {name=p289 lab=x65_D}
C {devices/lab_pin.sym} 2260 -300 0 0 {name=p290 lab=x65_E}
C {devices/lab_pin.sym} 2320 -260 0 0 {name=p291 lab=x65_R}
C {devices/lab_pin.sym} 2080 -200 0 1 {name=p292 lab=x66_Q}
C {devices/lab_pin.sym} 2080 -160 0 1 {name=p293 lab=x66_QB}
C {devices/lab_pin.sym} 1960 -200 0 0 {name=p294 lab=x66_D}
C {devices/lab_pin.sym} 1960 -160 0 0 {name=p295 lab=x66_E}
C {devices/lab_pin.sym} 2380 -470 0 1 {name=p296 lab=x67_Q}
C {devices/lab_pin.sym} 2260 -470 0 0 {name=p297 lab=x67_D}
C {devices/lab_pin.sym} 2260 -430 0 0 {name=p298 lab=x67_E}
C {devices/lab_pin.sym} 2320 -390 0 0 {name=p299 lab=x67_R}
C {devices/lab_pin.sym} 2380 -200 0 1 {name=p300 lab=x68_Q}
C {devices/lab_pin.sym} 2380 -160 0 1 {name=p301 lab=x68_QB}
C {devices/lab_pin.sym} 2260 -200 0 0 {name=p302 lab=x68_D}
C {devices/lab_pin.sym} 2260 -160 0 0 {name=p303 lab=x68_E}
C {devices/lab_pin.sym} 2320 -120 0 0 {name=p304 lab=x68_R}
C {devices/lab_pin.sym} 2080 -600 0 1 {name=p305 lab=x69_Q}
C {devices/lab_pin.sym} 1960 -600 0 0 {name=p306 lab=x69_D}
C {devices/lab_pin.sym} 1960 -560 0 0 {name=p307 lab=x69_E}
C {devices/lab_pin.sym} 2680 -600 0 1 {name=p308 lab=x62_Q}
C {devices/lab_pin.sym} 2560 -600 0 0 {name=p309 lab=x62_D}
C {devices/lab_pin.sym} 2560 -560 0 0 {name=p310 lab=x62_E}
C {devices/lab_pin.sym} 2620 -640 0 0 {name=p311 lab=x62_S}
C {devices/lab_pin.sym} 2680 -340 0 1 {name=p312 lab=x70_Q}
C {devices/lab_pin.sym} 2680 -300 0 1 {name=p313 lab=x70_QB}
C {devices/lab_pin.sym} 2560 -340 0 0 {name=p314 lab=x70_D}
C {devices/lab_pin.sym} 2560 -300 0 0 {name=p315 lab=x70_E}
C {devices/lab_pin.sym} 2620 -380 0 0 {name=p316 lab=x70_S}
C {devices/lab_pin.sym} 2680 -470 0 1 {name=p317 lab=x71_Q}
C {devices/lab_pin.sym} 2560 -470 0 0 {name=p318 lab=x71_D}
C {devices/lab_pin.sym} 2560 -430 0 0 {name=p319 lab=x71_E}
C {devices/lab_pin.sym} 2620 -510 0 0 {name=p320 lab=x71_S}
C {devices/lab_pin.sym} 2680 -200 0 1 {name=p321 lab=x72_Q}
C {devices/lab_pin.sym} 2680 -160 0 1 {name=p322 lab=x72_QB}
C {devices/lab_pin.sym} 2560 -200 0 0 {name=p323 lab=x72_D}
C {devices/lab_pin.sym} 2560 -160 0 0 {name=p324 lab=x72_E}
C {devices/lab_pin.sym} 2620 -240 0 0 {name=p325 lab=x72_S}
C {devices/lab_pin.sym} 2380 -770 0 1 {name=p326 lab=x73_Q}
C {devices/lab_pin.sym} 2260 -770 0 0 {name=p327 lab=x73_D}
C {devices/lab_pin.sym} 2260 -750 0 0 {name=p328 lab=x73_E}
C {devices/lab_pin.sym} 2260 -730 0 0 {name=p329 lab=x73_C}
C {devices/lab_pin.sym} 2380 -930 0 1 {name=p330 lab=x74_Q}
C {devices/lab_pin.sym} 2380 -890 0 1 {name=p331 lab=x74_QB}
C {devices/lab_pin.sym} 2260 -930 0 0 {name=p332 lab=x74_D}
C {devices/lab_pin.sym} 2260 -910 0 0 {name=p333 lab=x74_E}
C {devices/lab_pin.sym} 2260 -890 0 0 {name=p334 lab=x74_C}
C {devices/lab_pin.sym} 2080 -770 0 1 {name=p335 lab=x75_Q}
C {devices/lab_pin.sym} 1960 -790 0 0 {name=p336 lab=x75_SD}
C {devices/lab_pin.sym} 1960 -770 0 0 {name=p337 lab=x75_D}
C {devices/lab_pin.sym} 1960 -750 0 0 {name=p338 lab=x75_E}
C {devices/lab_pin.sym} 1960 -730 0 0 {name=p339 lab=x75_C}
C {devices/lab_pin.sym} 2080 -930 0 1 {name=p340 lab=x76_Q}
C {devices/lab_pin.sym} 2080 -890 0 1 {name=p341 lab=x76_QB}
C {devices/lab_pin.sym} 1960 -950 0 0 {name=p342 lab=x76_SD}
C {devices/lab_pin.sym} 1960 -930 0 0 {name=p343 lab=x76_D}
C {devices/lab_pin.sym} 1960 -910 0 0 {name=p344 lab=x76_E}
C {devices/lab_pin.sym} 1960 -890 0 0 {name=p345 lab=x76_C}
